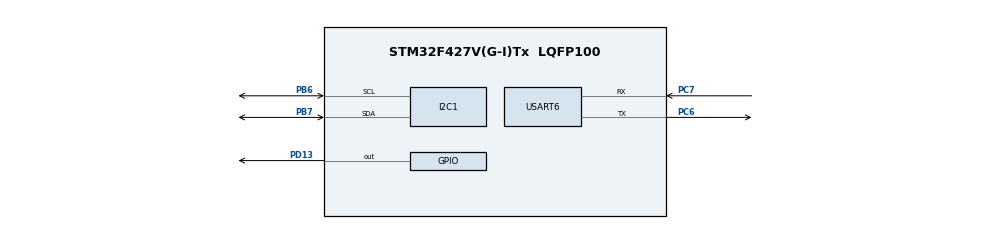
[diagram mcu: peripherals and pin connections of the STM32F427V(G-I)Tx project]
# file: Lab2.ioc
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Mcu.Family=STM32F4
Mcu.Name=STM32F427V(G-I)Tx
Mcu.Package=LQFP100
NVIC.PriorityGroup=NVIC_PRIORITYGROUP_4
PA13.Mode=JTAG_5_pins
PA13.Signal=SYS_JTMS-SWDIO
PA14.Mode=JTAG_5_pins
PA14.Signal=SYS_JTCK-SWCLK
PA15.Mode=JTAG_5_pins
PA15.Signal=SYS_JTDI
PB3.Mode=JTAG_5_pins
PB3.Signal=SYS_JTDO-SWO
PB4.Mode=JTAG_5_pins
PB4.Signal=SYS_JTRST
PB6.Mode=I2C
PB6.Signal=I2C1_SCL
PB7.Mode=I2C
PB7.Signal=I2C1_SDA
PC6.Mode=Asynchronous
PC6.Signal=USART6_TX
PC7.Mode=Asynchronous
PC7.Signal=USART6_RX
PD13.Signal=GPIO_Output
PH0/OSC_IN.Mode=HSE-External-Oscillator
PH0/OSC_IN.Signal=RCC_OSC_IN
PH1/OSC_OUT.Mode=HSE-External-Oscillator
PH1/OSC_OUT.Signal=RCC_OSC_OUT
ProjectManager.HeapSize=0x200
ProjectManager.StackSize=0x400
ProjectManager.TargetToolchain=STM32CubeIDE
RCC.AHBFreq_Value=16000000
RCC.APB1Freq_Value=16000000
RCC.APB2Freq_Value=16000000
RCC.CortexFreq_Value=16000000
RCC.HSE_VALUE=25000000
RCC.HSI_VALUE=16000000
RCC.LSE_VALUE=32768
RCC.SYSCLKFreq_VALUE=16000000
RCC.VCOOutputFreq_Value=192000000
USART6.VirtualMode=VM_ASYNC
board=custom

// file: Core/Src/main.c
/* USER CODE BEGIN Header */
/**
 ******************************************************************************
 * @file           : main.c
 * @brief          : Main program body
 ******************************************************************************
 * @attention
 *
 * <h2><center>&copy; Copyright (c) 2019 STMicroelectronics.
 * All rights reserved.</center></h2>
 *
 * This software component is licensed by ST under BSD 3-Clause license,
 * the "License"; You may not use this file except in compliance with the
 * License. You may obtain a copy of the License at:
 *                        opensource.org/licenses/BSD-3-Clause
 *
 ******************************************************************************
 */
/* USER CODE END Header */

#include "main.h"
#include "i2c.h"
#include "usart.h"
#include "gpio.h"
#include "calc.h"

/* USER CODE BEGIN Includes */
#include "kb.h"
#include "sdk_uart.h"
#include "pca9538.h"
#include "oled.h"
#include "fonts.h"

#include <stdlib.h>
/* USER CODE END Includes */

void SystemClock_Config(void);
/* USER CODE BEGIN PFP */
void KB_Test(void);
void OLED_KB(uint8_t OLED_Keys[]);
void oled_Reset(void);
/* USER CODE END PFP */

int main(void) {

	/* MCU Configuration--------------------------------------------------------*/

	/* Reset of all peripherals, Initializes the Flash interface and the Systick. */
	HAL_Init();

	/* Configure the system clock */
	SystemClock_Config();

	/* Initialize all configured peripherals */
	MX_GPIO_Init();
	MX_I2C1_Init();
	MX_USART6_UART_Init();
	/* USER CODE BEGIN 2 */
	oled_Init();

	oled_Reset();
	/* USER CODE END 2 */

	/* Infinite loop */
	while (1) {

		/* USER CODE BEGIN 3 */
		run();
	}
	/* USER CODE END 3 */
}

void SystemClock_Config(void) {
	RCC_OscInitTypeDef RCC_OscInitStruct = { 0 };
	RCC_ClkInitTypeDef RCC_ClkInitStruct = { 0 };

	/** Configure the main internal regulator output voltage
	 */
	__HAL_RCC_PWR_CLK_ENABLE();
	__HAL_PWR_VOLTAGESCALING_CONFIG(PWR_REGULATOR_VOLTAGE_SCALE1);
	/** Initializes the CPU, AHB and APB busses clocks
	 */
	RCC_OscInitStruct.OscillatorType = RCC_OSCILLATORTYPE_HSE;
	RCC_OscInitStruct.HSEState = RCC_HSE_ON;
	RCC_OscInitStruct.PLL.PLLState = RCC_PLL_ON;
	RCC_OscInitStruct.PLL.PLLSource = RCC_PLLSOURCE_HSE;
	RCC_OscInitStruct.PLL.PLLM = 25;
	RCC_OscInitStruct.PLL.PLLN = 336;
	RCC_OscInitStruct.PLL.PLLP = RCC_PLLP_DIV2;
	RCC_OscInitStruct.PLL.PLLQ = 4;
	if (HAL_RCC_OscConfig(&RCC_OscInitStruct) != HAL_OK) {
		Error_Handler();
	}
	/** Initializes the CPU, AHB and APB busses clocks
	 */
	RCC_ClkInitStruct.ClockType = RCC_CLOCKTYPE_HCLK | RCC_CLOCKTYPE_SYSCLK
			| RCC_CLOCKTYPE_PCLK1 | RCC_CLOCKTYPE_PCLK2;
	RCC_ClkInitStruct.SYSCLKSource = RCC_SYSCLKSOURCE_PLLCLK;
	RCC_ClkInitStruct.AHBCLKDivider = RCC_SYSCLK_DIV1;
	RCC_ClkInitStruct.APB1CLKDivider = RCC_HCLK_DIV4;
	RCC_ClkInitStruct.APB2CLKDivider = RCC_HCLK_DIV2;

	if (HAL_RCC_ClockConfig(&RCC_ClkInitStruct, FLASH_LATENCY_5) != HAL_OK) {
		Error_Handler();
	}
}

void Error_Handler(void) {
}

/************************ (C) COPYRIGHT STMicroelectronics *****END OF FILE****/
